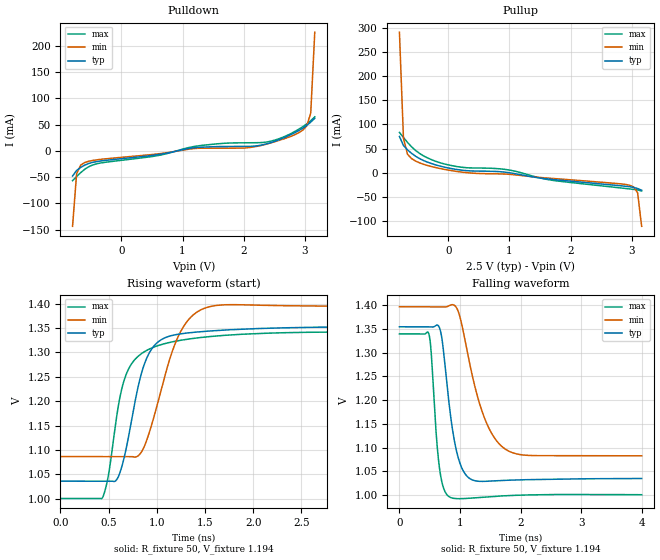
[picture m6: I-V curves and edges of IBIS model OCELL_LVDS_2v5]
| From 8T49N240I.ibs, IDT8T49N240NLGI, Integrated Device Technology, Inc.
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[Model] OCELL_LVDS_2v5
Model_type   Output
Polarity   Non-Inverting
|   typ   min   max
C_comp   2pF   1.5pF   2.5pF
Vmeas = 1.220V
Rref = 50
Cref = 0
Vref = 1.220V
|   typ   min   max
[Voltage range]   2.5V   2.375V   2.625V
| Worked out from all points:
|   slope of the pulldown table from 0 to 0.375 V, typ, clamps not added: 83 ohm
|   slope of the pullup table from 0 to 0.375 V, typ, clamps not added: 61.5 ohm
|   rising waveform, R_fixture 50, V_fixture 1.194: 20-80 % time 221ps typ, 279ps min, 212ps max; typ from 1.04 V to 1.35 V
|   falling waveform, R_fixture 50, V_fixture 1.194: 20-80 % time 193ps typ, 389ps min, 111ps max; typ from 1.35 V to 1.03 V
[Pulldown]
|Voltage   I (typ)   I (min)   I (max)
|Note, modeling breaks down at 250mA and above.  This is well beyond the functional   |
|operating range of the device.  Should this scenario occur, catastrophic failure and   |
|possible damage to the device and/or board is of higher concern than the I-V curve   |
|behavior.  The IBIS checker will flag currents in excess of 10A with warnings.  Lines   |
|with currents in excess of 0.35 A have been commented out.  The points still remain|
|available to the user if the user desires to use them.   |
|-2.20000e+00   -1.47097e+01   -1.29808e+01   -1.76557e+01
|-1.90000e+00   -1.13733e+01   -1.02041e+01   -1.33908e+01
|-1.60000e+00   -8.03533e+00   -7.42692e+00   -9.12248e+00
|-1.30000e+00   -4.69562e+00   -4.64912e+00   -4.85108e+00
|-1.00000e+00   -1.35574e+00   -1.87089e+00   -5.85237e-01
|-9.99000e-01   -1.34461e+00   -1.86163e+00   -5.71031e-01
|-9.32920e-01   -6.09702e-01   -1.24976e+00   -9.70404e-02
|-8.66839e-01   -1.10958e-01   -6.38044e-01   -6.49693e-02
-800.8mV  -47.82mA   -143.5mA   -56.56mA
-734.7mV  -37.16mA   -43.61mA   -48.81mA
-668.6mV  -31.47mA   -26.92mA   -41.41mA
-602.5mV  -27.08mA   -22.13mA   -35.03mA
-404.3mV  -20.22mA   -16.95mA   -24.39mA
1.248V    6.689mA    4.973mA    9.519mA
2.239V    10.01mA    9.203mA    15.71mA
2.569V    20.9mA     19.69mA    22.83mA
2.966V    43.07mA    39.48mA    46.04mA
3.032V    48.47mA    47.31mA    51.33mA
3.098V    54.8mA     72.05mA    57.5mA
3.164V    62.17mA    225.9mA    64.87mA
| 3.23015e+00   7.11206e-02   1.08222e+00   7.34598e-02
| 3.29623e+00   8.78340e-02   2.33437e+00   8.32765e-02
| 3.36231e+00   2.00703e-01   3.58979e+00   9.41196e-02
| 3.42839e+00   1.13807e+00   4.84535e+00   1.04227e-01
| 3.49447e+00   2.64416e+00   6.10108e+00   1.14469e-01
| 3.56055e+00   4.15263e+00   7.35698e+00   1.81917e-01
| 3.62663e+00   5.66131e+00   8.61307e+00   1.22175e+00
| 3.69271e+00   7.17020e+00   9.86935e+00   3.14969e+00
| 3.75879e+00   8.67931e+00   1.11258e+01   5.07876e+00
| 3.82487e+00   1.01886e+01   1.23825e+01   7.00809e+00
| 3.89095e+00   1.16982e+01   1.36393e+01   8.93770e+00
| 3.95703e+00   1.32079e+01   1.48964e+01   1.08676e+01
| 4.02311e+00   1.47179e+01   1.61536e+01   1.27977e+01
| 4.08920e+00   1.62280e+01   1.74110e+01   1.47281e+01
| 4.15528e+00   1.77384e+01   1.86686e+01   1.66587e+01
| 4.22136e+00   1.92490e+01   1.99264e+01   1.85896e+01
| 4.28744e+00   2.07598e+01   2.11844e+01   2.05207e+01
| 4.35352e+00   2.22708e+01   2.24426e+01   2.24520e+01
| 4.41960e+00   2.37820e+01   2.37010e+01   2.43836e+01
| 4.48568e+00   2.52934e+01   2.49596e+01   2.63155e+01
| 4.55176e+00   2.68050e+01   2.62184e+01   2.82475e+01
| 4.61784e+00   2.83168e+01   2.74774e+01   3.01798e+01
| 4.68392e+00   2.98287e+01   2.87366e+01   3.21123e+01
| 4.75000e+00   3.13409e+01   2.99961e+01   3.40450e+01
| 4.75100e+00   3.13638e+01   3.00151e+01   3.40742e+01
| 4.80080e+00   3.25035e+01   3.09644e+01   3.55309e+01
| 4.85060e+00   3.36434e+01   3.19139e+01   3.69877e+01
| 4.90040e+00   3.47833e+01   3.28634e+01   3.84446e+01
| 4.95020e+00   3.59234e+01   3.38131e+01   3.99016e+01
| 5.00000e+00   3.70636e+01   3.47629e+01   4.13587e+01
[Pullup]
|Voltage   I (typ)   I (min)   I (max)
|Note, modeling breaks down at 250mA and above.  This is well beyond the functional   |
|operating range of the device.  Should this scenario occur, catastrophic failure and   |
|possible damage to the device and/or board is of higher concern than the I-V curve   |
|behavior.  The IBIS checker will flag currents in excess of 10A with warnings.  Lines   |
|with currents in excess of 0.35 A have been commented out.  The points still remain|
|available to the user if the user desires to use them.   |
|-2.20000e+00   3.02063e+01   2.66718e+01   3.62465e+01
|-1.90000e+00   2.33374e+01   2.09532e+01   2.74674e+01
|-1.60000e+00   1.64734e+01   1.52383e+01   1.86947e+01
|-1.30000e+00   9.61386e+00   9.52791e+00   9.92385e+00
|-1.00000e+00   2.75851e+00   3.82202e+00   1.15949e+00
|-9.99000e-01   2.73566e+00   3.80301e+00   1.13131e+00
|-9.32920e-01   1.22633e+00   2.54675e+00   1.56550e-01
|-8.66839e-01   2.08726e-01   1.29062e+00   9.47517e-02
-800.8mV  75.03mA    290.8mA    83.5mA
-734.7mV  56.42mA    71.25mA    73.01mA
-668.6mV  47.38mA    38.24mA    62.73mA
-602.5mV  40.2mA     29.35mA    53.77mA
-338.2mV  21.78mA    14.85mA    30.53mA
58.29mV   8.387mA    4.174mA    14.67mA
917.3mV   1.313mA    -2.676mA   7.083mA
1.644V    -13.15mA   -11.21mA   -14.51mA
2.966V    -28.93mA   -25.91mA   -33.54mA
3.032V    -30.34mA   -29.4mA    -34.5mA
3.098V    -32.71mA   -41.22mA   -35.68mA
3.164V    -36.2mA    -110.9mA   -37.73mA
| 3.23015e+00   -4.09011e-02   -5.29071e-01   -4.13477e-02
| 3.29623e+00   -4.96629e-02   -1.13851e+00   -4.64521e-02
| 3.36231e+00   -1.02382e-01   -1.74810e+00   -5.25723e-02
| 3.42839e+00   -5.58991e-01   -2.35781e+00   -5.87606e-02
| 3.49447e+00   -1.29163e+00   -2.96762e+00   -6.53316e-02
| 3.56055e+00   -2.02440e+00   -3.57752e+00   -9.86556e-02
| 3.62663e+00   -2.75729e+00   -4.18750e+00   -6.04442e-01
| 3.69271e+00   -3.49028e+00   -4.79755e+00   -1.54167e+00
| 3.75879e+00   -4.22338e+00   -5.40769e+00   -2.47902e+00
| 3.82487e+00   -4.95656e+00   -6.01789e+00   -3.41649e+00
| 3.89095e+00   -5.68984e+00   -6.62816e+00   -4.35405e+00
| 3.95703e+00   -6.42319e+00   -7.23850e+00   -5.29170e+00
| 4.02311e+00   -7.15661e+00   -7.84890e+00   -6.22943e+00
| 4.08920e+00   -7.89011e+00   -8.45936e+00   -7.16724e+00
| 4.15528e+00   -8.62366e+00   -9.06989e+00   -8.10510e+00
| 4.22136e+00   -9.35728e+00   -9.68049e+00   -9.04301e+00
| 4.28744e+00   -1.00910e+01   -1.02912e+01   -9.98098e+00
| 4.35352e+00   -1.08247e+01   -1.09020e+01   -1.09190e+01
| 4.41960e+00   -1.15585e+01   -1.15129e+01   -1.18570e+01
| 4.48568e+00   -1.22923e+01   -1.21239e+01   -1.27952e+01
| 4.55176e+00   -1.30262e+01   -1.27352e+01   -1.37333e+01
| 4.61784e+00   -1.37602e+01   -1.33465e+01   -1.46715e+01
| 4.68392e+00   -1.44942e+01   -1.39579e+01   -1.56097e+01
| 4.75000e+00   -1.52283e+01   -1.45694e+01   -1.65480e+01
| 4.75100e+00   -1.52394e+01   -1.45786e+01   -1.65622e+01
| 4.80080e+00   -1.57928e+01   -1.50395e+01   -1.72694e+01
| 4.85060e+00   -1.63462e+01   -1.55004e+01   -1.79765e+01
| 4.90040e+00   -1.68997e+01   -1.59614e+01   -1.86837e+01
| 4.95020e+00   -1.74533e+01   -1.64223e+01   -1.93909e+01
| 5.00000e+00   -1.80069e+01   -1.68833e+01   -2.00981e+01
[Ramp]
|   typ   min   max
dV/dt_r   0.191/0.221n   0.187/0.287n   0.205/0.213n
dV/dt_f   0.197/0.201n   0.19/0.391n   0.21/0.116n
R_load =   50.0000
[Rising Waveform]
R_fixture = 50
V_fixture   =1.194  |Vcc_typ
V_fixture_min=1.238  |Vcc_min
V_fixture_max=1.171  |Vcc_max
C_fixture = 0.0p
| Time   typ   min   max
0s        1.036V     1.086V     1V
435.6ps   1.036V     1.086V     1.002V
497.8ps   1.036V     1.086V     1.048V
586.7ps   1.04V      1.086V     1.173V
711.1ps   1.132V     1.086V     1.268V
831.1ps   1.25V      1.093V     1.296V
946.7ps   1.307V     1.152V     1.309V
1.213ns   1.337V     1.329V     1.324V
1.484ns   1.343V     1.39V      1.331V
4ns       1.354V     1.393V     1.341V
[Falling Waveform]
R_fixture = 50
V_fixture   =1.194  |Vcc_typ
V_fixture_min=1.238  |Vcc_min
V_fixture_max=1.171  |Vcc_max
C_fixture = 0.0p
| Time   typ   min   max
0s        1.355V     1.397V     1.34V
484.4ps   1.354V     1.397V     1.34V
520ps     1.354V     1.397V     1.308V
657.8ps   1.353V     1.396V     1.061V
822.2ps   1.19V      1.399V     996.6mV
942.2ps   1.093V     1.395V     992.7mV
1.084ns   1.045V     1.325V     993mV
1.378ns   1.029V     1.172V     995.7mV
1.716ns   1.031V     1.1V       998.5mV
4ns       1.035V     1.083V     1.001V
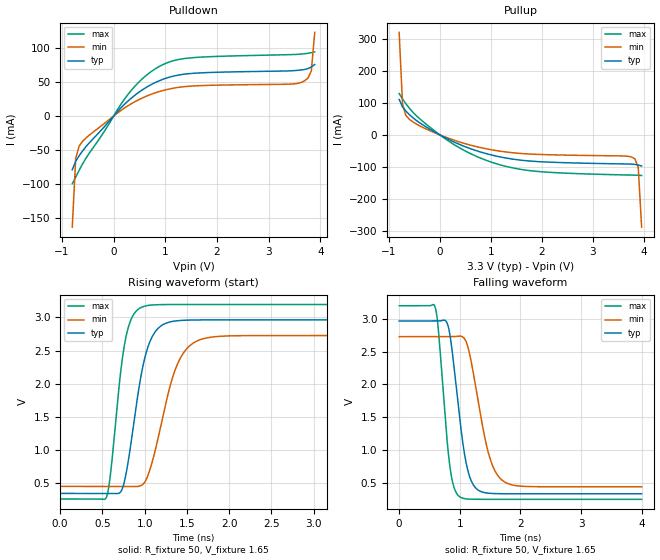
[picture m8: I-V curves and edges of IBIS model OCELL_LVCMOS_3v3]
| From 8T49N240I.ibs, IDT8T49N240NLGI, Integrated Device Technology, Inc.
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[Model] OCELL_LVCMOS_3v3
Model_type   Output
Polarity   Non-Inverting
|   typ   min   max
C_comp   2pF   1.5pF   2.5pF
Vmeas = 1.65V
Rref = 50
Cref = 0
Vref = 1.65V
|   typ   min   max
[Voltage range]   3.3V   3.135V   3.465V
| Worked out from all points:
|   slope of the pulldown table from 0 to 0.495 V, typ, clamps not added: 14 ohm
|   slope of the pullup table from 0 to 0.495 V, typ, clamps not added: 13.5 ohm
|   rising waveform, R_fixture 50, V_fixture 1.65: 20-80 % time 201ps typ, 272ps min, 150ps max; typ from 0.339 V to 2.96 V
|   falling waveform, R_fixture 50, V_fixture 1.65: 20-80 % time 209ps typ, 286ps min, 158ps max; typ from 2.96 V to 0.339 V
[Pulldown]
|Voltage   I (typ)   I (min)   I (max)
|Note, modeling breaks down at 250mA and above.  This is well beyond the functional   |
|operating range of the device.  Should this scenario occur, catastrophic failure and   |
|possible damage to the device and/or board is of higher concern than the I-V curve   |
|behavior.  The IBIS checker will flag currents in excess of 10A with warnings.  Lines   |
|with currents in excess of 0.35 A have been commented out.  The points still remain|
|available to the user if the user desires to use them.   |
|-2.84000e+00   -2.18618e+01   -1.89356e+01   -2.67925e+01
|-2.38000e+00   -1.67450e+01   -1.46752e+01   -2.02542e+01
|-1.92000e+00   -1.16278e+01   -1.04147e+01   -1.37151e+01
|-1.46000e+00   -6.50924e+00   -6.15380e+00   -7.17503e+00
|-1.00000e+00   -1.38985e+00   -1.89239e+00   -6.32776e-01
|-9.99000e-01   -1.37872e+00   -1.88313e+00   -6.18548e-01
|-9.32920e-01   -6.43376e-01   -1.27100e+00   -1.43288e-01
|-8.66839e-01   -1.43698e-01   -6.58927e-01   -1.09838e-01
-800.8mV  -79.19mA   -163.8mA   -99.82mA
-734.7mV  -66.64mA   -62.75mA   -90mA
-668.6mV  -58.66mA   -44.34mA   -80.08mA
-470.4mV  -39.43mA   -28.11mA   -54.54mA
322.6mV   25.13mA    17.23mA    36.11mA
653mV     43.18mA    29.82mA    61.27mA
983.4mV   54.9mA     38.17mA    76.8mA
1.578V    63.12mA    44.44mA    86.22mA
3.627V    67.8mA     49.4mA     91.26mA
3.759V    69.87mA    55.79mA    92.44mA
3.825V    72.28mA    66.47mA    93.27mA
3.891V    75.91mA    123.3mA    94.54mA
| 3.95703e+00   8.07890e-02   5.40024e-01   9.69756e-02
| 4.02311e+00   8.72919e-02   1.71267e+00   1.00957e-01
| 4.08920e+00   1.00248e-01   2.96728e+00   1.06477e-01
| 4.15528e+00   1.87103e-01   4.22206e+00   1.13479e-01
| 4.22136e+00   9.98623e-01   5.47704e+00   1.21618e-01
| 4.28744e+00   2.49607e+00   6.73222e+00   1.29268e-01
| 4.35352e+00   4.00375e+00   7.98760e+00   1.41886e-01
| 4.41960e+00   5.51170e+00   9.24319e+00   2.99700e-01
| 4.48568e+00   7.01990e+00   1.04990e+01   1.79680e+00
| 4.55176e+00   8.52837e+00   1.17550e+01   3.72520e+00
| 4.61784e+00   1.00371e+01   1.30112e+01   5.65397e+00
| 4.68392e+00   1.15461e+01   1.42676e+01   7.58310e+00
| 4.75000e+00   1.30554e+01   1.55243e+01   9.51259e+00
| 4.75100e+00   1.30783e+01   1.55433e+01   9.54180e+00
| 5.12080e+00   2.15300e+01   2.25799e+01   2.03466e+01
| 5.49060e+00   2.99915e+01   2.96242e+01   3.11638e+01
| 5.86040e+00   3.84640e+01   3.66775e+01   4.19933e+01
| 6.23020e+00   4.69485e+01   4.37415e+01   5.28295e+01
| 6.60000e+00   5.54425e+01   5.08180e+01   6.36657e+01
[Pullup]
|Voltage   I (typ)   I (min)   I (max)
|Note, modeling breaks down at 250mA and above.  This is well beyond the functional   |
|operating range of the device.  Should this scenario occur, catastrophic failure and   |
|possible damage to the device and/or board is of higher concern than the I-V curve   |
|behavior.  The IBIS checker will flag currents in excess of 10A with warnings.  Lines   |
|with currents in excess of 0.35 A have been commented out.  The points still remain|
|available to the user if the user desires to use them.   |
|-2.84000e+00   4.49430e+01   3.89394e+01   5.50801e+01
|-2.38000e+00   3.43996e+01   3.01620e+01   4.16047e+01
|-1.92000e+00   2.38611e+01   2.13880e+01   2.81347e+01
|-1.46000e+00   1.33293e+01   1.26207e+01   1.46716e+01
|-1.00000e+00   2.80313e+00   3.85890e+00   1.21565e+00
|-9.99000e-01   2.78026e+00   3.83986e+00   1.18742e+00
|-9.32920e-01   1.26846e+00   2.58147e+00   2.09793e-01
|-8.66839e-01   2.48041e-01   1.32294e+00   1.44643e-01
-800.8mV  110.7mA    320.1mA    129mA
-734.7mV  87.5mA     96.82mA    112.6mA
-668.6mV  74.48mA    60.62mA    97.24mA
-602.5mV  63.83mA    48.98mA    83.78mA
-272.1mV  25.1mA     18.63mA    33.72mA
256.5mV   -20.63mA   -15.34mA   -28.09mA
1.116V    -66.35mA   -49.09mA   -90.25mA
1.975V    -83.61mA   -61mA      -114.7mA
3.759V    -91.01mA   -68.75mA   -125.3mA
3.825V    -91.89mA   -74.48mA   -125.5mA
3.891V    -93.78mA   -101.9mA   -125.8mA
3.957V    -96.83mA   -287.7mA   -126.6mA
| 4.02311e+00   -1.01131e-01   -8.75415e-01   -1.28580e-01
| 4.08920e+00   -1.08942e-01   -1.48560e+00   -1.32255e-01
| 4.15528e+00   -1.50873e-01   -2.09597e+00   -1.37411e-01
| 4.22136e+00   -5.42515e-01   -2.70648e+00   -1.43596e-01
| 4.28744e+00   -1.27564e+00   -3.31712e+00   -1.49905e-01
| 4.35352e+00   -2.00899e+00   -3.92786e+00   -1.58752e-01
| 4.41960e+00   -2.74255e+00   -4.53869e+00   -2.33411e-01
| 4.48568e+00   -3.47631e+00   -5.14961e+00   -9.65831e-01
| 4.55176e+00   -4.21025e+00   -5.76062e+00   -1.90376e+00
| 4.61784e+00   -4.94435e+00   -6.37170e+00   -2.84183e+00
| 4.68392e+00   -5.67857e+00   -6.98287e+00   -3.78000e+00
| 4.75000e+00   -6.41292e+00   -7.59411e+00   -4.71828e+00
| 4.75100e+00   -6.42403e+00   -7.60336e+00   -4.73247e+00
| 5.12080e+00   -1.05354e+01   -1.10254e+01   -9.98649e+00
| 5.49060e+00   -1.46497e+01   -1.44497e+01   -1.52457e+01
| 5.86040e+00   -1.87674e+01   -1.78767e+01   -2.05097e+01
| 6.23020e+00   -2.28899e+01   -2.13073e+01   -2.57804e+01
| 6.60000e+00   -2.70190e+01   -2.47426e+01   -3.10607e+01
[Ramp]
|   typ   min   max
dV/dt_r   1.576/0.201n   1.37/0.272n   1.767/0.15n
dV/dt_f   1.583/0.21n   1.374/0.286n   1.776/0.158n
R_load =   50.0000
[Rising Waveform]
R_fixture = 50
V_fixture = 1.65   |Vcc_typ
V_fixture_min = 1.5675 |Vcc_min
V_fixture_max = 1.7325 |Vcc_max
C_fixture = 0.0p
| Time   typ   min   max
0s        339.3mV    445.3mV    254.7mV
546.7ps   339.4mV    445.3mV    278.7mV
595.6ps   339.6mV    445.3mV    631.9mV
764.4ps   544mV      445.5mV    2.612V
946.7ps   2.047V     453.1mV    3.144V
1.036ns   2.542V     602.5mV    3.181V
1.147ns   2.819V     1.107V     3.193V
1.364ns   2.948V     2.221V     3.196V
1.591ns   2.963V     2.626V     3.196V
4ns       2.964V     2.727V     3.196V
[Falling Waveform]
R_fixture = 50
V_fixture = 1.65   |Vcc_typ
V_fixture_min = 1.5675 |Vcc_min
V_fixture_max = 1.7325 |Vcc_max
C_fixture = 0.0p
| Time   typ   min   max
0s        2.964V     2.727V     3.196V
595.6ps   2.964V     2.727V     3.169V
648.9ps   2.964V     2.727V     2.811V
813.3ps   2.869V     2.727V     939.3mV
991.1ps   1.55V      2.736V     299.3mV
1.098ns   841.8mV    2.664V     262.2mV
1.209ns   498.6mV    2.249V     255.9mV
1.467ns   348.1mV    979.7mV    254.7mV
1.698ns   340mV      545.9mV    254.7mV
4ns       339.3mV    445.3mV    254.7mV
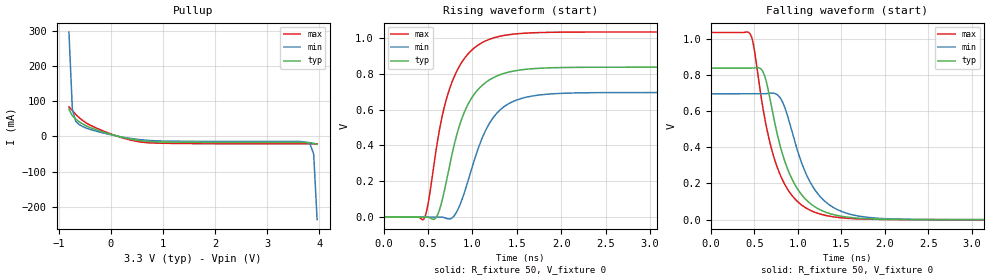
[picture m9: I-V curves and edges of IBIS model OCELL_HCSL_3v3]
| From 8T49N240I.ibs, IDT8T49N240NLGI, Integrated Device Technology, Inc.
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[Model] OCELL_HCSL_3v3
Model_type   Open_source
Polarity   Non-Inverting
|   typ   min   max
C_comp   2pF   1.5pF   2.5pF
Vmeas = 0.409V
Rref = 50
Cref = 0
Vref = 0V
|   typ   min   max
[Voltage range]   3.3V   3.135V   3.465V
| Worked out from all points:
|   slope of the pullup table from 0 to 0.495 V, typ, clamps not added: 30.3 ohm
|   rising waveform, R_fixture 50, V_fixture 0: 20-80 % time 304ps typ, 325ps min, 294ps max; typ from 0 V to 0.837 V
|   falling waveform, R_fixture 50, V_fixture 0: 20-80 % time 320ps typ, 344ps min, 303ps max; typ from 0.837 V to 0 V
[Pullup]
|Voltage   I (typ)   I (min)   I (max)
|Note, modeling breaks down at 250mA and above.  This is well beyond the functional   |
|operating range of the device.  Should this scenario occur, catastrophic failure and   |
|possible damage to the device and/or board is of higher concern than the I-V curve   |
|behavior.  The IBIS checker will flag currents in excess of 10A with warnings.  Lines   |
|with currents in excess of 0.35 A have been commented out.  The points still remain|
|available to the user if the user desires to use them.   |
|-2.84000e+00   4.48689e+01   3.88862e+01   5.49818e+01
|-2.38000e+00   3.43280e+01   3.01097e+01   4.15125e+01
|-1.92000e+00   2.37959e+01   2.13390e+01   2.80532e+01
|-1.46000e+00   1.32738e+01   1.25783e+01   1.46006e+01
|-1.00000e+00   2.76073e+00   3.82758e+00   1.15971e+00
|-9.99000e-01   2.73789e+00   3.80857e+00   1.13152e+00
|-9.32920e-01   1.22854e+00   2.55221e+00   1.56844e-01
|-8.66839e-01   2.10884e-01   1.29593e+00   9.50659e-02
-800.8mV  77.04mA    295.9mA    83.69mA
-734.7mV  58.15mA    75.99mA    72.85mA
-668.6mV  48.85mA    42.64mA    62.2mA
-602.5mV  41.43mA    33.41mA    52.89mA
-404.3mV  25.71mA    20.39mA    32.78mA
-73.87mV  9.266mA    7.482mA    11.45mA
256.5mV   -3.581mA   -2.5mA     -5.356mA
586.9mV   -12.13mA   -9.37mA    -15.9mA
3.759V    -16.99mA   -17.01mA   -20.75mA
3.825V    -17.71mA   -22.64mA   -20.76mA
3.891V    -19.44mA   -49.95mA   -20.85mA
3.957V    -22.33mA   -235.6mA   -21.4mA
| 4.02311e+00   -2.64829e-02   -8.23295e-01   -2.31929e-02
| 4.08920e+00   -3.41448e-02   -1.43339e+00   -2.66471e-02
| 4.15528e+00   -7.59303e-02   -2.04367e+00   -3.15857e-02
| 4.22136e+00   -4.67429e-01   -2.65409e+00   -3.75564e-02
| 4.28744e+00   -1.20042e+00   -3.26463e+00   -4.36540e-02
| 4.35352e+00   -1.93363e+00   -3.87528e+00   -5.22880e-02
| 4.41960e+00   -2.66705e+00   -4.48602e+00   -1.26729e-01
| 4.48568e+00   -3.40067e+00   -5.09684e+00   -8.58924e-01
| 4.55176e+00   -4.13447e+00   -5.70775e+00   -1.79662e+00
| 4.61784e+00   -4.86841e+00   -6.31873e+00   -2.73443e+00
| 4.68392e+00   -5.60247e+00   -6.92978e+00   -3.67234e+00
| 4.75000e+00   -6.33663e+00   -7.54090e+00   -4.61032e+00
| 4.75100e+00   -6.34774e+00   -7.55015e+00   -4.62452e+00
| 5.12080e+00   -1.04577e+01   -1.09712e+01   -9.87650e+00
| 5.49060e+00   -1.45694e+01   -1.43937e+01   -1.51318e+01
| 5.86040e+00   -1.86820e+01   -1.78173e+01   -2.03880e+01
| 6.23020e+00   -2.27953e+01   -2.12419e+01   -2.56448e+01
| 6.60000e+00   -2.69092e+01   -2.46671e+01   -3.09019e+01
[Ramp]
|   typ   min   max
dV/dt_r   0.51/0.305n   0.423/0.327n   0.629/0.294n
dV/dt_f   0.504/0.319n   0.419/0.344n   0.622/0.303n
R_load =   50.0000
[Rising Waveform]
R_fixture = 50
V_fixture = 0   | VCC_typ
V_fixture_max = 0   | VCC_max
V_fixture_min = 0   | VCC_min
C_fixture = 0.0p
| Time   typ   min   max
0s        24.01nV    17.59nV    43.74nV
457.8ps   10.57uV    -769.7nV   -7.335mV
506.7ps   -1.68mV    594.5nV    89.98mV
604.4ps   8.48mV     6.649uV    416.7mV
742.2ps   285.3mV    -10.84mV   715.7mV
906.7ps   582.7mV    132.2mV    883.9mV
1.12ns    739.8mV    452.8mV    977.1mV
1.338ns   799.6mV    609.2mV    1.013V
1.676ns   828.6mV    676.1mV    1.029V
4ns       837.1mV    695.5mV    1.034V
[Falling Waveform]
R_fixture = 50
V_fixture = 0   | VCC_typ
V_fixture_max = 0   | VCC_max
V_fixture_min = 0   | VCC_min
C_fixture = 0.0p
| Time   typ   min   max
0s        837.1mV    695.4mV    1.034V
457.8ps   836.9mV    695.4mV    1.022V
497.8ps   838.1mV    695.4mV    948mV
608.9ps   807.9mV    695.4mV    591.2mV
742.2ps   520.4mV    696.4mV    320mV
906.7ps   252.5mV    534.3mV    151mV
1.12ns    99.2mV     228.3mV    57.63mV
1.356ns   35.69mV    84.59mV    20.03mV
1.711ns   7.705mV    19.08mV    4.081mV
4ns       386.1nV    1.338uV    167.9nV
